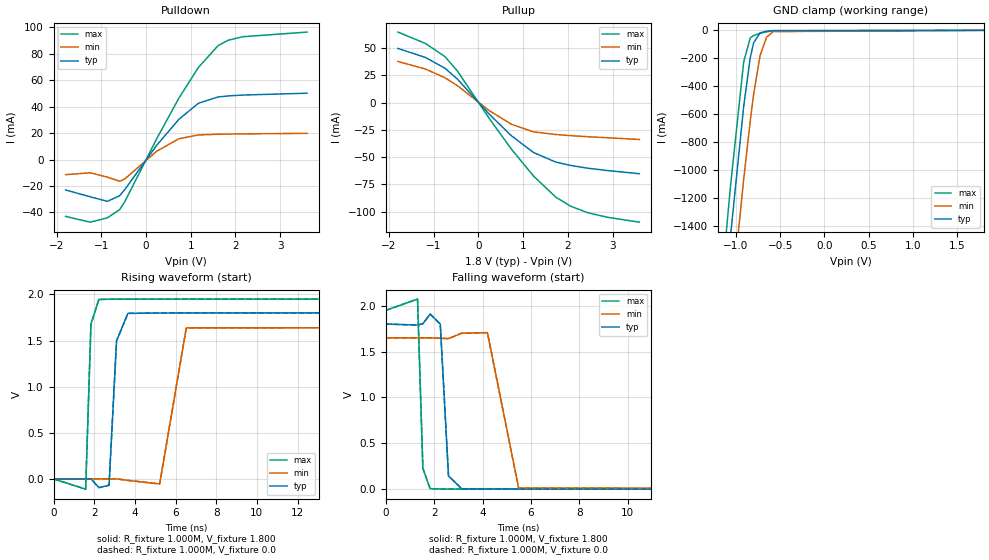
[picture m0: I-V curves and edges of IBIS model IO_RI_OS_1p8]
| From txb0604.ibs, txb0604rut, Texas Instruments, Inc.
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|   Model IO_RI_OS_1p8
[Model] IO_RI_OS_1p8
Model_type 3-state
Polarity   Non-Inverting
Enable   Active-High
Vmeas =  0.900V
Cref =  0.100nF
Rref =  1.000M
Vref =  0.0V
C_comp   3.790pF   3.490pF   3.980pF
[Temperature Range]   27.000   0.125k   -40.000
[Voltage Range]   1.800V   1.650V   1.950V
[Pullup Reference]   1.800V   1.650V   1.950V
[Pulldown Reference]   0.0V   0.0V   0.0V
[POWER Clamp Reference]   1.800V   1.650V   1.950V
[GND Clamp Reference]   0.0V   0.0V   0.0V
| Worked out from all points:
|   slope of the pulldown table from 0 to 0.27 V, typ, clamps not added: 22.1 ohm
|   slope of the pullup table from 0 to 0.27 V, typ, clamps not added: 22.7 ohm
|   GND clamp passes 1 mA (typ) near -0.55 V on its own axis
|   rising waveform, R_fixture 1.000M, V_fixture 1.800: 20-80 % time 218ps typ, 360ps min, 143ps max; typ from 0 V to 1.8 V
|   rising waveform, R_fixture 1.000M, V_fixture 0.0: 20-80 % time 218ps typ, 360ps min, 143ps max; typ from 0 V to 1.8 V
|   falling waveform, R_fixture 1.000M, V_fixture 1.800: 20-80 % time 181ps typ, 353ps min, 111ps max; typ from 1.8 V to 0 V
|   falling waveform, R_fixture 1.000M, V_fixture 0.0: 20-80 % time 181ps typ, 353ps min, 111ps max; typ from 1.8 V to 0 V
[Pulldown]
|Voltage   I(typ)   I(min)   I(max)
-1.8V     -23mA      -11.42mA   -42.98mA
-1.25V    -28.14mA   -9.971mA   -47.37mA
-865mV    -31.61mA   -13.31mA   -44.05mA
-590mV    -27.3mA    -16.43mA   -37.87mA
-480mV    -22.89mA   -14.75mA   -32.12mA
235mV     10.7mA     6.25mA     15.61mA
730mV     30.33mA    15.72mA    46.24mA
1.17V     42.62mA    18.65mA    69.7mA
1.61V     47.38mA    19.17mA    86.19mA
1.83V     48.15mA    19.3mA     90.23mA
2.16V     48.82mA    19.45mA    92.96mA
3.6V      50.23mA    19.86mA    96.47mA
[Pullup]
|Voltage   I(typ)   I(min)   I(max)
-1.8V     49.5mA     37.57mA    64.49mA
-1.185V   41.29mA    30.68mA    54.09mA
-745mV    31.3mA     22.59mA    41.92mA
-470mV    21.49mA    15.44mA    28.86mA
245mV     -10.81mA   -7.521mA   -14.77mA
740mV     -30.5mA    -19.95mA   -42.8mA
1.235V    -45.83mA   -26.89mA   -67.43mA
1.73V     -54.55mA   -29.3mA    -86.62mA
2.06V     -57.59mA   -30.35mA   -94.92mA
2.445V    -60.16mA   -31.32mA   -100.9mA
2.885V    -62.3mA    -32.27mA   -105.1mA
3.6V      -65.21mA   -33.84mA   -109.6mA
[GND_clamp]
|Voltage   I(typ)   I(min)   I(max)
-1.8V     -6.737A    -7.122A    -6.527A
-1.208V   -2.479A    -2.984A    -2.145A
-1.171V   -2.222A    -2.734A    -1.881A
-1.134V   -1.967A    -2.486A    -1.62A
-1.06V    -1.466A    -1.996A    -1.109A
-912mV    -545.1mA   -1.066A    -226.6mA
-838mV    -197.5mA   -649mA     -54.23mA
-801mV    -91.44mA   -464.4mA   -37.71mA
-727mV    -18.24mA   -180.9mA   -21.59mA
-653mV    -6.339mA   -48.93mA   -10.39mA
-579mV    -1.938mA   -9.115mA   -3.32mA
1.8V      0A         0A         0A
[Ramp]
| variable   typ   min   max
dV/dt_r   1.080/0.217n   0.990/0.359n   1.170/0.142n
dV/dt_f   1.080/0.181n   0.990/0.357n   1.170/0.110n
R_load = 1.000M
[Rising Waveform]
R_fixture= 1.000M
V_fixture= 1.800
V_fixture_min= 1.650
V_fixture_max= 1.950
|time   V(typ)   V(min)   V(max)
0s        36.34uV    56.32uV    26.53uV
1.58ns    -288.8uV   52.58uV    -111.2mV
1.84ns    1.177mV    31.62uV    1.678V
2.23ns    -94.74mV   -53.15uV   1.946V
2.73ns    -68.57mV   -274.5uV   1.948V
3.1ns     1.497V     544.8uV    1.949V
3.66ns    1.795V     -16.08mV   1.949V
5.22ns    1.799V     -54.47mV   1.95V
6.53ns    1.8V       1.638V     1.95V
120ns     1.8V       1.65V      1.95V
[Rising Waveform]
R_fixture= 1.000M
V_fixture= 0.0
V_fixture_min= 0.0
V_fixture_max= 0.0
|time   V(typ)   V(min)   V(max)
0s        -1.92uV    -1.519uV   -2.312uV
1.58ns    -327.6uV   -5.201uV   -111.3mV
1.84ns    1.139mV    -26.08uV   1.677V
2.23ns    -94.83mV   -110.5uV   1.946V
2.73ns    -68.81mV   -332.3uV   1.948V
3.1ns     1.497V     485.7uV    1.949V
3.66ns    1.795V     -16.14mV   1.949V
5.22ns    1.799V     -54.96mV   1.95V
6.53ns    1.8V       1.638V     1.95V
120ns     1.8V       1.65V      1.95V
[Falling Waveform]
R_fixture= 1.000M
V_fixture= 1.800
V_fixture_min= 1.650
V_fixture_max= 1.950
|time   V(typ)   V(min)   V(max)
0s        1.8V       1.65V      1.95V
1.31ns    1.79V      1.65V      2.073V
1.53ns    1.804V     1.65V      228.5mV
1.83ns    1.909V     1.651V     5.293mV
2.25ns    1.8V       1.645V     1.924mV
2.59ns    145.1mV    1.642V     1.284mV
3.14ns    3.446mV    1.701V     805.5uV
4.2ns     986.8uV    1.707V     271.2uV
5.49ns    434uV      10.81mV    88.89uV
120ns     38.37uV    58.15uV    28.92uV
[Falling Waveform]
R_fixture= 1.000M
V_fixture= 0.0
V_fixture_min= 0.0
V_fixture_max= 0.0
|time   V(typ)   V(min)   V(max)
0s        1.8V       1.65V      1.95V
1.31ns    1.79V      1.65V      2.073V
1.53ns    1.804V     1.65V      228.4mV
1.83ns    1.909V     1.65V      5.264mV
2.25ns    1.8V       1.645V     1.895mV
2.59ns    145mV      1.642V     1.256mV
3.14ns    3.407mV    1.701V     776.7uV
4.2ns     948.5uV    1.706V     242.4uV
5.49ns    395.7uV    10.74mV    60.04uV
120ns     93.7nV     299.2nV    65.71nV
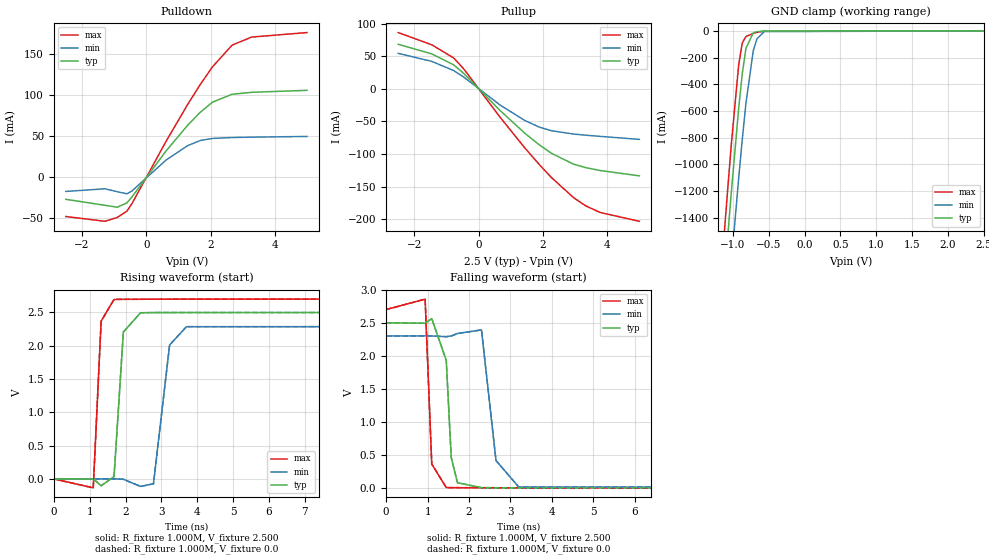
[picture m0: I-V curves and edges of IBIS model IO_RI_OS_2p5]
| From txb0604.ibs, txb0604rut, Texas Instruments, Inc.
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|   Model IO_RI_OS_2p5
[Model] IO_RI_OS_2p5
Model_type 3-state
Polarity   Non-Inverting
Enable   Active-High
Vmeas =  1.250V
Cref =  0.100nF
Rref =  1.000M
Vref =  0.0V
C_comp   3.670pF   3.390pF   3.920pF
[Temperature Range]   27.000   0.125k   -40.000
[Voltage Range]   2.500V   2.300V   2.700V
[Pullup Reference]   2.500V   2.300V   2.700V
[Pulldown Reference]   0.0V   0.0V   0.0V
[POWER Clamp Reference]   2.500V   2.300V   2.700V
[GND Clamp Reference]   0.0V   0.0V   0.0V
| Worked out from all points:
|   slope of the pulldown table from 0 to 0.375 V, typ, clamps not added: 18.9 ohm
|   slope of the pullup table from 0 to 0.375 V, typ, clamps not added: 19.8 ohm
|   GND clamp passes 1 mA (typ) near -0.54 V on its own axis
|   rising waveform, R_fixture 1.000M, V_fixture 2.500: 20-80 % time 159ps typ, 236ps min, 119ps max; typ from 0 V to 2.5 V
|   rising waveform, R_fixture 1.000M, V_fixture 0.0: 20-80 % time 159ps typ, 236ps min, 119ps max; typ from 0 V to 2.5 V
|   falling waveform, R_fixture 1.000M, V_fixture 2.500: 20-80 % time 121ps typ, 217ps min, 87.9ps max; typ from 2.5 V to 0 V
|   falling waveform, R_fixture 1.000M, V_fixture 0.0: 20-80 % time 121ps typ, 217ps min, 87.9ps max; typ from 2.5 V to 0 V
[Pulldown]
|Voltage   I(typ)   I(min)   I(max)
-2.5V     -26.95mA   -17.31mA   -47.93mA
-1.284V   -34.24mA   -14.08mA   -53.76mA
-904mV    -36.57mA   -17.67mA   -49.09mA
-600mV    -31.21mA   -20.16mA   -41.35mA
-448mV    -24.18mA   -16.81mA   -32.37mA
616mV     32.11mA    20.99mA    43.87mA
1.3V      64.04mA    38.83mA    89.66mA
1.68V     79.29mA    44.89mA    113.2mA
2.06V     91.65mA    47.37mA    134.8mA
2.668V    101.3mA    48.47mA    161.2mA
3.276V    103.7mA    48.94mA    171.1mA
5V        106.1mA    49.8mA     176.6mA
[Pullup]
|Voltage   I(typ)   I(min)   I(max)
-2.5V     68.55mA    54.59mA    86.52mA
-1.46V    53.85mA    42.31mA    67.83mA
-776mV    36.91mA    28.15mA    47.54mA
-472mV    24.25mA    18.47mA    31.29mA
668mV     -33.22mA   -24.76mA   -43.53mA
1.428V    -67.65mA   -48.29mA   -90.12mA
1.884V    -85.82mA   -58.66mA   -116mA
2.264V    -98.87mA   -64.23mA   -136.1mA
2.948V    -115.5mA   -69.36mA   -166.8mA
3.328V    -120.9mA   -71.13mA   -179.6mA
3.784V    -125.4mA   -72.95mA   -189.9mA
5V        -133.6mA   -77.54mA   -203.4mA
[GND_clamp]
|Voltage   I(typ)   I(min)   I(max)
-2.5V     -11.36A    -11.16A    -11.58A
-1.174V   -2.242A    -2.754A    -1.903A
-1.123V   -1.891A    -2.412A    -1.543A
-1.072V   -1.546A    -2.075A    -1.19A
-1.021V   -1.21A     -1.743A    -850mA
-919mV    -584.2mA   -1.108A    -257.8mA
-868mV    -320.7mA   -811.8mA   -90.35mA
-817mV    -130.7mA   -541.5mA   -43.06mA
-715mV    -15mA      -149.4mA   -19.5mA
-664mV    -7.355mA   -60.49mA   -11.8mA
-562mV    -1.371mA   -6.057mA   -2.317mA
2.5V      0A         0A         0A
[Ramp]
| variable   typ   min   max
dV/dt_r   1.500/0.159n   1.380/0.237n   1.620/0.115n
dV/dt_f   1.500/0.127n   1.380/0.217n   1.620/86.181p
R_load = 1.000M
[Rising Waveform]
R_fixture= 1.000M
V_fixture= 2.500
V_fixture_min= 2.300
V_fixture_max= 2.700
|time   V(typ)   V(min)   V(max)
0s        43.55uV    60.08uV    33.94uV
1.1ns     807.1uV    -43.86uV   -134.5mV
1.32ns    -103.2mV   -202uV     2.369V
1.68ns    34.15mV    302.8uV    2.695V
1.94ns    2.206V     -5.501mV   2.697V
2.42ns    2.495V     -113.4mV   2.698V
2.78ns    2.498V     -72.55mV   2.699V
3.23ns    2.498V     2.011V     2.699V
3.7ns     2.499V     2.286V     2.7V
120ns     2.5V       2.3V       2.7V
[Rising Waveform]
R_fixture= 1.000M
V_fixture= 0.0
V_fixture_min= 0.0
V_fixture_max= 0.0
|time   V(typ)   V(min)   V(max)
0s        -2.635uV   -2.155uV   -3.116uV
1.1ns     760.5uV    -105.8uV   -134.6mV
1.32ns    -103.3mV   -263.5uV   2.369V
1.68ns    33.94mV    239.3uV    2.695V
1.94ns    2.206V     -5.563mV   2.697V
2.42ns    2.495V     -113.6mV   2.698V
2.78ns    2.498V     -72.9mV    2.699V
3.23ns    2.498V     2.011V     2.699V
3.7ns     2.499V     2.286V     2.7V
120ns     2.5V       2.3V       2.7V
[Falling Waveform]
R_fixture= 1.000M
V_fixture= 2.500
V_fixture_min= 2.300
V_fixture_max= 2.700
|time   V(typ)   V(min)   V(max)
0s        2.5V       2.3V       2.7V
940ps     2.493V     2.301V     2.858V
1.1ns     2.563V     2.3V       360.9mV
1.45ns    1.931V     2.289V     4.847mV
1.57ns    461.3mV    2.3V       3.54mV
1.72ns    77.82mV    2.337V     2.794mV
2.3ns     2.943mV    2.392V     1.458mV
2.65ns    1.983mV    414.1mV    1.054mV
3.2ns     1.297mV    11.66mV    532.8uV
120ns     46.29uV    62.53uV    37.14uV
[Falling Waveform]
R_fixture= 1.000M
V_fixture= 0.0
V_fixture_min= 0.0
V_fixture_max= 0.0
|time   V(typ)   V(min)   V(max)
0s        2.5V       2.3V       2.7V
940ps     2.493V     2.301V     2.858V
1.1ns     2.563V     2.3V       360.8mV
1.45ns    1.931V     2.289V     4.81mV
1.57ns    461.2mV    2.3V       3.503mV
1.72ns    77.76mV    2.337V     2.757mV
2.3ns     2.897mV    2.392V     1.421mV
2.65ns    1.936mV    413.9mV    1.017mV
3.2ns     1.251mV    11.59mV    495.7uV
120ns     88.09nV    280.4nV    60.11nV
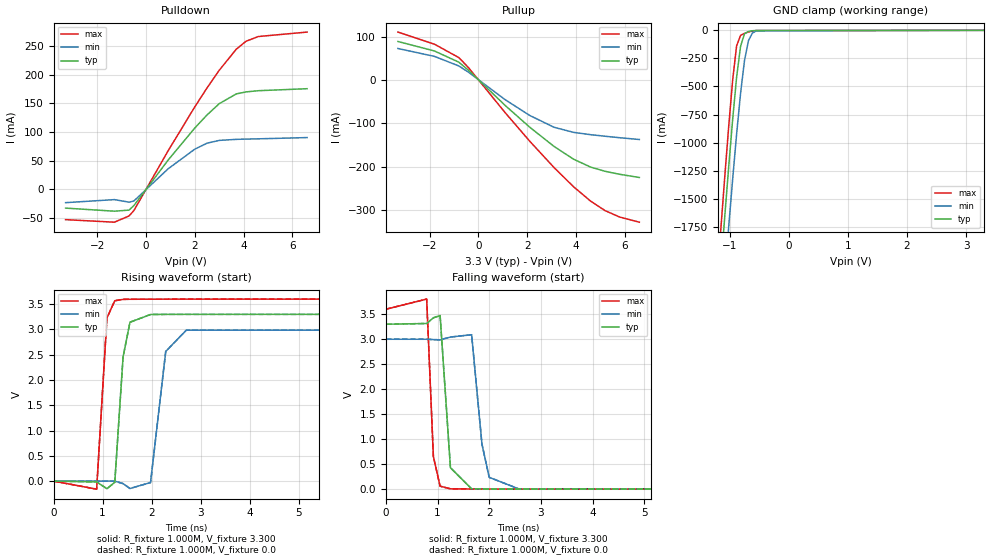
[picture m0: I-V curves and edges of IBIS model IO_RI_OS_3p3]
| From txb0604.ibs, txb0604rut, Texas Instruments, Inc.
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|   Model IO_RI_OS_3p3
[Model] IO_RI_OS_3p3
Model_type 3-state
Polarity   Non-Inverting
Enable   Active-High
Vmeas =  1.650V
Cref =  0.100nF
Rref =  1.000M
Vref =  0.0V
C_comp   3.560pF   3.290pF   3.850pF
[Temperature Range]   27.000   0.125k   -40.000
[Voltage Range]   3.300V   3.000V   3.600V
[Pullup Reference]   3.300V   3.000V   3.600V
[Pulldown Reference]   0.0V   0.0V   0.0V
[POWER Clamp Reference]   3.300V   3.000V   3.600V
[GND Clamp Reference]   0.0V   0.0V   0.0V
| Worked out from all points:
|   slope of the pulldown table from 0 to 0.495 V, typ, clamps not added: 17.5 ohm
|   slope of the pullup table from 0 to 0.495 V, typ, clamps not added: 18.4 ohm
|   GND clamp passes 1 mA (typ) near -0.54 V on its own axis
|   rising waveform, R_fixture 1.000M, V_fixture 3.300: 20-80 % time 135ps typ, 188ps min, 105ps max; typ from 0 V to 3.3 V
|   rising waveform, R_fixture 1.000M, V_fixture 0.0: 20-80 % time 135ps typ, 188ps min, 105ps max; typ from 0 V to 3.3 V
|   falling waveform, R_fixture 1.000M, V_fixture 3.300: 20-80 % time 101ps typ, 163ps min, 75.3ps max; typ from 3.3 V to 0 V
|   falling waveform, R_fixture 1.000M, V_fixture 0.0: 20-80 % time 101ps typ, 163ps min, 75.3ps max; typ from 3.3 V to 0 V
[Pulldown]
|Voltage   I(typ)   I(min)   I(max)
-3.3V     -33.08mA   -23.56mA   -53.27mA
-1.3V     -38.48mA   -18.23mA   -57.72mA
-700mV    -36.61mA   -22.68mA   -46.88mA
-500mV    -28.71mA   -20.69mA   -37.39mA
900mV     50.62mA    35.46mA    66.8mA
2V        107.1mA    70.03mA    144.1mA
2.5V      129.8mA    80.47mA    177mA
3V        149.5mA    85.3mA     207.9mA
3.7V      166.6mA    87.12mA    244.8mA
4.1V      170.1mA    87.6mA     258.7mA
4.6V      172.2mA    88.04mA    266.9mA
6.6V      175.7mA    90.25mA    274.7mA
[Pullup]
|Voltage   I(typ)   I(min)   I(max)
-3.3V     88.66mA    72.5mA     110.3mA
-1.8V     66.73mA    54.27mA    82.29mA
-800mV    40.9mA     32.22mA    51.49mA
-400mV    22.07mA    17.54mA    28.03mA
1.1V      -58.86mA   -45.55mA   -75.51mA
2.1V      -108.6mA   -81.62mA   -140.8mA
3.1V      -153.1mA   -109mA     -201.7mA
3.9V      -182.5mA   -120.7mA   -245.9mA
4.6V      -200.7mA   -126.1mA   -279.1mA
5.2V      -210.5mA   -129.7mA   -301.2mA
5.8V      -217.4mA   -133.1mA   -316mA
6.6V      -224.7mA   -137.2mA   -327.7mA
[GND_clamp]
|Voltage   I(typ)   I(min)   I(max)
-3.3V     -15.16A    -14.83A    -15.52A
-1.156V   -2.118A    -2.633A    -1.775A
-1.089V   -1.661A    -2.187A    -1.307A
-1.022V   -1.216A    -1.75A     -856.6mA
-955mV    -794.8mA   -1.327A    -443.9mA
-888mV    -417.7mA   -925.5mA   -138.1mA
-821mV    -142.1mA   -561.7mA   -44.71mA
-754mV    -30.52mA   -267.7mA   -26.73mA
-687mV    -10.01mA   -92.37mA   -15.03mA
-620mV    -3.936mA   -24.04mA   -6.702mA
-553mV    -1.125mA   -4.87mA    -1.879mA
3.3V      0A         0A         0A
[Ramp]
| variable   typ   min   max
dV/dt_r   1.980/0.134n   1.800/0.186n   2.160/0.102n
dV/dt_f   1.980/0.104n   1.800/0.166n   2.160/74.809p
R_load = 1.000M
[Rising Waveform]
R_fixture= 1.000M
V_fixture= 3.300
V_fixture_min= 3.000
V_fixture_max= 3.600
|time   V(typ)   V(min)   V(max)
0s        53.57uV    68.65uV    43.61uV
880ps     -15.22mV   -200.8uV   -158.9mV
1.09ns    -150.3mV   -337.5uV   3.226V
1.25ns    -22.42mV   735.1uV    3.567V
1.42ns    2.46V      -50.08mV   3.594V
1.56ns    3.142V     -145.6mV   3.596V
1.98ns    3.295V     -28mV      3.597V
2.29ns    3.297V     2.564V     3.598V
2.71ns    3.298V     2.984V     3.599V
120ns     3.3V       3V         3.6V
[Rising Waveform]
R_fixture= 1.000M
V_fixture= 0.0
V_fixture_min= 0.0
V_fixture_max= 0.0
|time   V(typ)   V(min)   V(max)
0s        -3.371uV   -2.772uV   -3.989uV
880ps     -15.28mV   -272.3uV   -159mV
1.09ns    -150.5mV   -409.6uV   3.226V
1.25ns    -22.65mV   663.2uV    3.567V
1.42ns    2.459V     -50.16mV   3.594V
1.56ns    3.142V     -145.7mV   3.596V
1.98ns    3.295V     -28.36mV   3.597V
2.29ns    3.297V     2.564V     3.598V
2.71ns    3.298V     2.984V     3.599V
120ns     3.3V       3V         3.6V
[Falling Waveform]
R_fixture= 1.000M
V_fixture= 3.300
V_fixture_min= 3.000
V_fixture_max= 3.600
|time   V(typ)   V(min)   V(max)
0s        3.3V       3V         3.6V
790ps     3.315V     3V         3.804V
920ps     3.429V     2.993V     651.9mV
1.05ns    3.474V     2.988V     60.09mV
1.25ns    429.6mV    3.044V     6.787mV
1.66ns    6.573mV    3.09V      2.993mV
1.86ns    3.967mV    900.5mV    2.342mV
2ns       3.298mV    237.3mV    2.072mV
2.57ns    1.962mV    6.114mV    1.078mV
120ns     57.05uV    71.76uV    47.67uV
[Falling Waveform]
R_fixture= 1.000M
V_fixture= 0.0
V_fixture_min= 0.0
V_fixture_max= 0.0
|time   V(typ)   V(min)   V(max)
0s        3.3V       3V         3.6V
790ps     3.315V     3V         3.804V
920ps     3.429V     2.993V     651.8mV
1.05ns    3.474V     2.988V     60.04mV
1.25ns    429.5mV    3.044V     6.739mV
1.66ns    6.516mV    3.09V      2.946mV
1.86ns    3.911mV    900.3mV    2.294mV
2ns       3.241mV    237.1mV    2.025mV
2.57ns    1.905mV    6.042mV    1.03mV
120ns     84.46nV    319.8nV    56.83nV
